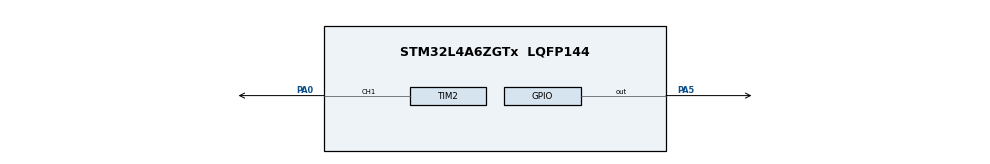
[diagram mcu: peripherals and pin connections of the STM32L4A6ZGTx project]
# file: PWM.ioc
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Mcu.Family=STM32L4
Mcu.Name=STM32L4A6ZGTx
Mcu.Package=LQFP144
NVIC.PriorityGroup=NVIC_PRIORITYGROUP_4
PA0.Signal=S_TIM2_CH1
PA5.PinState=GPIO_PIN_SET
PA5.Signal=GPIO_Output
PH0-OSC_IN\ (PH0).Mode=HSE-External-Oscillator
PH0-OSC_IN\ (PH0).Signal=RCC_OSC_IN
PH1-OSC_OUT\ (PH1).Mode=HSE-External-Oscillator
PH1-OSC_OUT\ (PH1).Signal=RCC_OSC_OUT
ProjectManager.HeapSize=0x200
ProjectManager.StackSize=0x400
ProjectManager.TargetToolchain=STM32CubeIDE
RCC.ADCFreq_Value=48000000
RCC.AHBFreq_Value=47333333.333333336
RCC.APB1CLKDivider=RCC_HCLK_DIV2
RCC.APB1Freq_Value=23666666.666666668
RCC.APB1TimFreq_Value=47333333.333333336
RCC.APB2Freq_Value=47333333.333333336
RCC.APB2TimFreq_Value=47333333.333333336
RCC.CortexFreq_Value=47333333.333333336
RCC.FLatency=FLASH_LATENCY_2
RCC.HCLKFreq_Value=47333333.333333336
RCC.HSE_VALUE=8000000
RCC.HSI48_VALUE=48000000
RCC.HSI_VALUE=16000000
RCC.MSI_VALUE=4000000
RCC.PLLN=71
RCC.PLLR=RCC_PLLR_DIV6
RCC.PLLSAI1N=24
RCC.SYSCLKFreq_VALUE=47333333.333333336
RCC.SYSCLKSource=RCC_SYSCLKSOURCE_PLLCLK
RCC.USBFreq_Value=48000000
RCC.VCOOutputFreq_Value=284000000
SH.S_TIM2_CH1.0=TIM2_CH1,PWM Generation1 CH1
TIM2.Channel-PWM\ Generation1\ CH1=TIM_CHANNEL_1
VP_TIM2_VS_ClockSourceINT.Mode=Internal
board=NUCLEO-L4A6ZG

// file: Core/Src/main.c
/* USER CODE BEGIN Header */
/**
  ******************************************************************************
  * @file           : main.c
  * @brief          : Main program body
  ******************************************************************************
  * @attention
  *
  * <h2><center>&copy; Copyright (c) 2024 STMicroelectronics.
  * All rights reserved.</center></h2>
  *
  * This software component is licensed by ST under BSD 3-Clause license,
  * the "License"; You may not use this file except in compliance with the
  * License. You may obtain a copy of the License at:
  *                        opensource.org/licenses/BSD-3-Clause
  *
  ******************************************************************************
  */
/* USER CODE END Header */
#include "main.h"

TIM_HandleTypeDef htim2;

void SystemClock_Config(void);
static void MX_GPIO_Init(void);
static void MX_TIM2_Init(void);

int main(void)
{

  /* MCU Configuration--------------------------------------------------------*/

  /* Reset of all peripherals, Initializes the Flash interface and the Systick. */
  HAL_Init();

  /* Configure the system clock */
  SystemClock_Config();

  /* Initialize all configured peripherals */
  MX_GPIO_Init();
  MX_TIM2_Init();
  /* USER CODE BEGIN 2 */

  /* Start PWM signal generation on TIM2 Channel 1 */
  HAL_TIM_PWM_Start(&htim2, TIM_CHANNEL_1);

  /* USER CODE END 2 */

  /* Infinite loop */
  /* USER CODE BEGIN WHILE */
  while (1)
  {
    for (uint32_t dutyCycle = 0; dutyCycle <= 1000; dutyCycle += 10)
    {
      __HAL_TIM_SET_COMPARE(&htim2, TIM_CHANNEL_1, dutyCycle);
      HAL_Delay(10);
    }

    for (uint32_t dutyCycle = 1000; dutyCycle > 0; dutyCycle -= 10)
    {
      __HAL_TIM_SET_COMPARE(&htim2, TIM_CHANNEL_1, dutyCycle);
      HAL_Delay(10);
    }
  }
  /* USER CODE END WHILE */

}

void SystemClock_Config(void)
{
  RCC_OscInitTypeDef RCC_OscInitStruct = {0};
  RCC_ClkInitTypeDef RCC_ClkInitStruct = {0};

  /** Configure the main internal regulator output voltage
  */
  if (HAL_PWREx_ControlVoltageScaling(PWR_REGULATOR_VOLTAGE_SCALE1) != HAL_OK)
  {
    Error_Handler();
  }

  /** Initializes the RCC Oscillators according to the specified parameters
  * in the RCC_OscInitTypeDef structure.
  */
  RCC_OscInitStruct.OscillatorType = RCC_OSCILLATORTYPE_MSI;
  RCC_OscInitStruct.MSIState = RCC_MSI_ON;
  RCC_OscInitStruct.MSICalibrationValue = 0;
  RCC_OscInitStruct.MSIClockRange = RCC_MSIRANGE_6;
  RCC_OscInitStruct.PLL.PLLState = RCC_PLL_ON;
  RCC_OscInitStruct.PLL.PLLSource = RCC_PLLSOURCE_MSI;
  RCC_OscInitStruct.PLL.PLLM = 1;
  RCC_OscInitStruct.PLL.PLLN = 40;
  RCC_OscInitStruct.PLL.PLLP = RCC_PLLP_DIV7;
  RCC_OscInitStruct.PLL.PLLQ = RCC_PLLQ_DIV2;
  RCC_OscInitStruct.PLL.PLLR = RCC_PLLR_DIV2;
  if (HAL_RCC_OscConfig(&RCC_OscInitStruct) != HAL_OK)
  {
    Error_Handler();
  }

  /** Initializes the CPU, AHB and APB buses clocks
  */
  RCC_ClkInitStruct.ClockType = RCC_CLOCKTYPE_HCLK|RCC_CLOCKTYPE_SYSCLK
                              |RCC_CLOCKTYPE_PCLK1|RCC_CLOCKTYPE_PCLK2;
  RCC_ClkInitStruct.SYSCLKSource = RCC_SYSCLKSOURCE_PLLCLK;
  RCC_ClkInitStruct.AHBCLKDivider = RCC_SYSCLK_DIV1;
  RCC_ClkInitStruct.APB1CLKDivider = RCC_HCLK_DIV1;
  RCC_ClkInitStruct.APB2CLKDivider = RCC_HCLK_DIV1;

  if (HAL_RCC_ClockConfig(&RCC_ClkInitStruct, FLASH_LATENCY_4) != HAL_OK)
  {
    Error_Handler();
  }
}

static void MX_TIM2_Init(void)
{

  TIM_ClockConfigTypeDef sClockSourceConfig = {0};
  TIM_MasterConfigTypeDef sMasterConfig = {0};
  TIM_OC_InitTypeDef sConfigOC = {0};

  htim2.Instance = TIM2;
  htim2.Init.Prescaler = 79;
  htim2.Init.CounterMode = TIM_COUNTERMODE_UP;
  htim2.Init.Period = 999;
  htim2.Init.ClockDivision = TIM_CLOCKDIVISION_DIV1;
  if (HAL_TIM_Base_Init(&htim2) != HAL_OK)
  {
    Error_Handler();
  }
  sClockSourceConfig.ClockSource = TIM_CLOCKSOURCE_INTERNAL;
  if (HAL_TIM_ConfigClockSource(&htim2, &sClockSourceConfig) != HAL_OK)
  {
    Error_Handler();
  }
  if (HAL_TIM_PWM_Init(&htim2) != HAL_OK)
  {
    Error_Handler();
  }
  sMasterConfig.MasterOutputTrigger = TIM_TRGO_RESET;
  sMasterConfig.MasterSlaveMode = TIM_MASTERSLAVEMODE_DISABLE;
  if (HAL_TIMEx_MasterConfigSynchronization(&htim2, &sMasterConfig) != HAL_OK)
  {
    Error_Handler();
  }
  sConfigOC.OCMode = TIM_OCMODE_PWM1;
  sConfigOC.Pulse = 0;
  sConfigOC.OCPolarity = TIM_OCPOLARITY_HIGH;
  sConfigOC.OCFastMode = TIM_OCFAST_DISABLE;
  if (HAL_TIM_PWM_ConfigChannel(&htim2, &sConfigOC, TIM_CHANNEL_1) != HAL_OK)
  {
    Error_Handler();
  }
  HAL_TIM_MspPostInit(&htim2);

}

static void MX_GPIO_Init(void)
{
  /* GPIO Ports Clock Enable */
  __HAL_RCC_GPIOC_CLK_ENABLE();
  __HAL_RCC_GPIOH_CLK_ENABLE();
  __HAL_RCC_GPIOA_CLK_ENABLE();

  /*Configure GPIO pin Output Level */
  HAL_GPIO_WritePin(GPIOA, GPIO_PIN_5, GPIO_PIN_RESET);

  /*Configure GPIO pin : PA5 */
  GPIO_InitTypeDef GPIO_InitStruct = {0};
  GPIO_InitStruct.Pin = GPIO_PIN_5;
  GPIO_InitStruct.Mode = GPIO_MODE_AF_PP;
  GPIO_InitStruct.Pull = GPIO_NOPULL;
  GPIO_InitStruct.Speed = GPIO_SPEED_FREQ_LOW;
  GPIO_InitStruct.Alternate = GPIO_AF1_TIM2;
  HAL_GPIO_Init(GPIOA, &GPIO_InitStruct);
}

void Error_Handler(void)
{
  __disable_irq();
  while (1)
  {
  }
}
